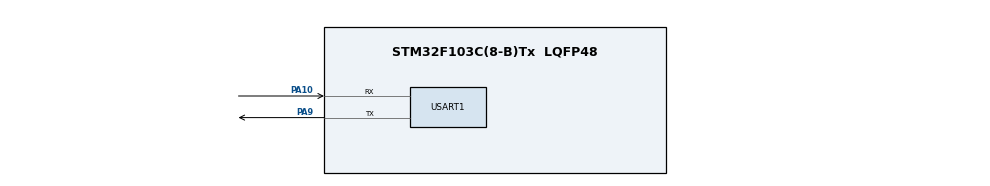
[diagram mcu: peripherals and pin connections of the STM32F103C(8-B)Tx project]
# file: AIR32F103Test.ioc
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Mcu.Family=STM32F1
Mcu.Name=STM32F103C(8-B)Tx
Mcu.Package=LQFP48
NVIC.PriorityGroup=NVIC_PRIORITYGROUP_4
PA10.Mode=Asynchronous
PA10.Signal=USART1_RX
PA13.Mode=Serial_Wire
PA13.Signal=SYS_JTMS-SWDIO
PA14.Mode=Serial_Wire
PA14.Signal=SYS_JTCK-SWCLK
PA9.Mode=Asynchronous
PA9.Signal=USART1_TX
PD0-OSC_IN.Mode=HSE-External-Oscillator
PD0-OSC_IN.Signal=RCC_OSC_IN
PD1-OSC_OUT.Mode=HSE-External-Oscillator
PD1-OSC_OUT.Signal=RCC_OSC_OUT
ProjectManager.HeapSize=0x200
ProjectManager.StackSize=0x400
ProjectManager.TargetToolchain=MDK-ARM V5.32
RCC.AHBFreq_Value=72000000
RCC.APB1CLKDivider=RCC_HCLK_DIV2
RCC.APB1Freq_Value=36000000
RCC.APB1TimFreq_Value=72000000
RCC.APB2Freq_Value=72000000
RCC.APB2TimFreq_Value=72000000
RCC.HCLKFreq_Value=72000000
RCC.PLLMUL=RCC_PLL_MUL9
RCC.PLLSourceVirtual=RCC_PLLSOURCE_HSE
RCC.SYSCLKFreq_VALUE=72000000
RCC.SYSCLKSource=RCC_SYSCLKSOURCE_PLLCLK
RCC.USBFreq_Value=72000000
USART1.VirtualMode=VM_ASYNC
board=custom

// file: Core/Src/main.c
/* USER CODE BEGIN Header */
/**
  ******************************************************************************
  * @file           : main.c
  * @brief          : Main program body
  ******************************************************************************
  * @attention
  *
  * Copyright (c) 2023 STMicroelectronics.
  * All rights reserved.
  *
  * This software is licensed under terms that can be found in the LICENSE file
  * in the root directory of this software component.
  * If no LICENSE file comes with this software, it is provided AS-IS.
  *
  ******************************************************************************
  */
/* USER CODE END Header */
#include "main.h"
#include "usart.h"
#include "gpio.h"

/* USER CODE BEGIN Includes */
#include "MyPrintf.h"
/* USER CODE END Includes */

void SystemClock_Config(void);
void MCO_Init(void);

int main(void)
{

  /* MCU Configuration--------------------------------------------------------*/

  /* Reset of all peripherals, Initializes the Flash interface and the Systick. */
  HAL_Init();

  /* Configure the system clock */
  SystemClock_Config();

  /* Initialize all configured peripherals */
  MX_GPIO_Init();
  MX_USART1_UART_Init();
  /* USER CODE BEGIN 2 */
  MyPrintf("Hello World!\n");
  MCO_Init();
  /* USER CODE END 2 */

  /* Infinite loop */
  while (1)
  {

    /* USER CODE BEGIN 3 */
    MyPrintf("SystemCoreClock: %d Hz\n", HAL_RCC_GetSysClockFreq());
    HAL_GPIO_TogglePin(GPIOB, GPIO_PIN_10);
    HAL_Delay(1000);
  }
  /* USER CODE END 3 */
}
#define SysFreq_Set     (*((void (*)(uint32_t, FlashClkDiv , uint8_t, uint8_t))(*(uint32_t *)0x1FFFD00C)))
void SystemClock_Config(void)
{
  RCC_OscInitTypeDef RCC_OscInitStruct = {0};
  RCC_ClkInitTypeDef RCC_ClkInitStruct = {0};
  /** Initializes the RCC Oscillators according to the specified parameters
  * in the RCC_OscInitTypeDef structure.
  */
  RCC_OscInitStruct.OscillatorType = RCC_OSCILLATORTYPE_HSE;
  RCC_OscInitStruct.HSEState = RCC_HSE_ON;
  RCC_OscInitStruct.HSEPredivValue = RCC_HSE_PREDIV_DIV1;
  RCC_OscInitStruct.HSIState = RCC_HSI_ON;
  RCC_OscInitStruct.PLL.PLLState = RCC_PLL_ON;
  RCC_OscInitStruct.PLL.PLLSource = RCC_PLLSOURCE_HSE;
  RCC_OscInitStruct.PLL.PLLMUL = RCC_PLL_MUL32;
  if (HAL_RCC_OscConfig(&RCC_OscInitStruct) != HAL_OK)
  {
    Error_Handler();
  }

  /** Initializes the CPU, AHB and APB buses clocks
  */
  RCC_ClkInitStruct.ClockType = RCC_CLOCKTYPE_HCLK|RCC_CLOCKTYPE_SYSCLK
                              |RCC_CLOCKTYPE_PCLK1|RCC_CLOCKTYPE_PCLK2;
  RCC_ClkInitStruct.SYSCLKSource = RCC_SYSCLKSOURCE_PLLCLK;
  RCC_ClkInitStruct.AHBCLKDivider = RCC_SYSCLK_DIV1;
  RCC_ClkInitStruct.APB1CLKDivider = RCC_HCLK_DIV2;
  RCC_ClkInitStruct.APB2CLKDivider = RCC_HCLK_DIV1;

  if (HAL_RCC_ClockConfig(&RCC_ClkInitStruct, FLASH_LATENCY_2) != HAL_OK)
  {
    Error_Handler();
  }
}

/* USER CODE BEGIN 4 */
void MCO_Init(void)
{
  HAL_RCC_MCOConfig(RCC_MCO1, RCC_MCO1SOURCE_PLLCLK_DIV16, RCC_MCODIV_1);
}
/* USER CODE END 4 */

void Error_Handler(void)
{
  __disable_irq();
  while (1)
  {
  }
}
